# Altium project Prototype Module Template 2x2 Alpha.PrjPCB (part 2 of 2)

## Sheet Host Comm.SchDoc: Host Communication
size B; Date: 12/18/2013; DrawnBy: David McCoy; Engineer: David McCoy (Cospan Design); DocumentNumber: 9; Revision: C; SheetNumber: 9; SheetTotal: 10

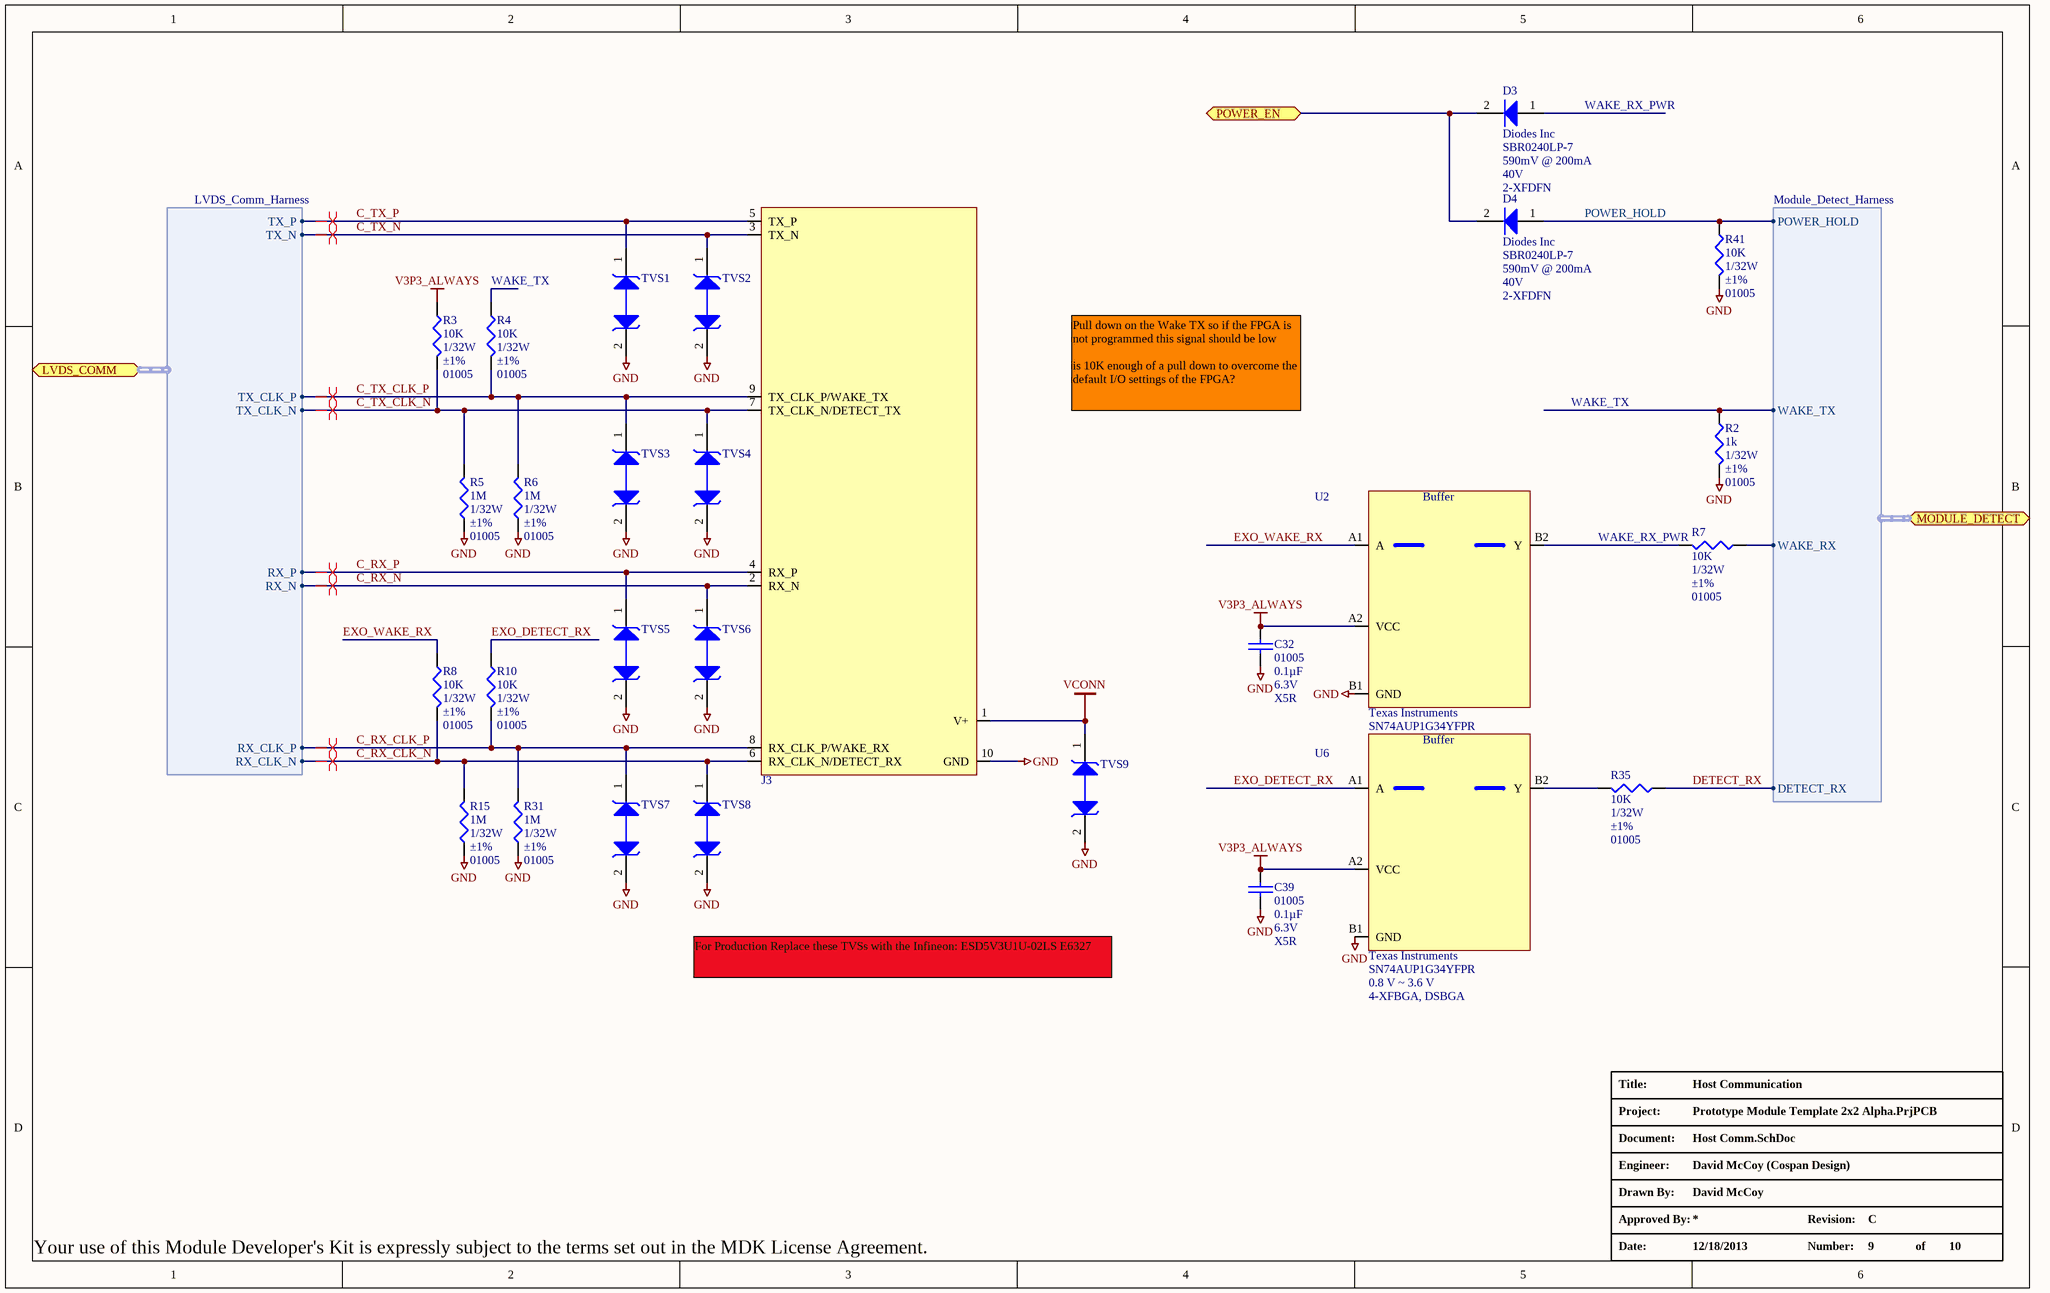
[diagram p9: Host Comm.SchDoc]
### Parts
C32  Package / Case: 01005  Capacitance: 0.1µF  Voltage - Rated: 6.3V  Temperature Coefficient: X5R  [C_01005]  (hidden comment: 0.1uF)
C39  Package / Case: 01005  Capacitance: 0.1µF  Voltage - Rated: 6.3V  Temperature Coefficient: X5R  [C_01005]  (hidden comment: 0.1uF)
D3  Manufacturer: Diodes Inc  Voltage - Forward (Vf) (Max) @ If: 590mV @ 200mA  Voltage - DC Reverse (Vr) (Max): 40V  [2-XFDFN]  (hidden comment: SBR0240LP-7)
D4  Manufacturer: Diodes Inc  Voltage - Forward (Vf) (Max) @ If: 590mV @ 200mA  Voltage - DC Reverse (Vr) (Max): 40V  [2-XFDFN]  (hidden comment: SBR0240LP-7)
J3  SPRING PIN  [10PIN SMD CONNECTOR]  (value not drawn)  (no BOM)
R2  Power (Watts): 1/32W  Tolerance: ±1%  Case: 01005  [R_01005]  (hidden comment: 1k)
R3  Power (Watts): 1/32W  Tolerance: ±1%  Case: 01005  [R_01005]  (hidden comment: 10K)
R4  Power (Watts): 1/32W  Tolerance: ±1%  Case: 01005  [R_01005]  (hidden comment: 10K)
R5  Resistance In Ohms: 1M  Power (Watts): 1/32W  Tolerance: ±1%  Case: 01005  [R_01005]  (hidden comment: 1M Ohms)
R6  Resistance In Ohms: 1M  Power (Watts): 1/32W  Tolerance: ±1%  Case: 01005  [R_01005]  (hidden comment: 1M Ohms)
R7  Power (Watts): 1/32W  Tolerance: ±1%  Case: 01005  [R_01005]  (hidden comment: 10K)
R8  Power (Watts): 1/32W  Tolerance: ±1%  Case: 01005  [R_01005]  (hidden comment: 10K)
R10  Power (Watts): 1/32W  Tolerance: ±1%  Case: 01005  [R_01005]  (hidden comment: 10K)
R15  Resistance In Ohms: 1M  Power (Watts): 1/32W  Tolerance: ±1%  Case: 01005  [R_01005]  (hidden comment: 1M Ohms)
R31  Resistance In Ohms: 1M  Power (Watts): 1/32W  Tolerance: ±1%  Case: 01005  [R_01005]  (hidden comment: 1M Ohms)
R35  Power (Watts): 1/32W  Tolerance: ±1%  Case: 01005  [R_01005]  (hidden comment: 10K)
R41  Power (Watts): 1/32W  Tolerance: ±1%  Case: 01005  [R_01005]  (hidden comment: 10K)
TVS1  TVS_ESDAVLC6-1BV2  [ST_MICRO_TVS]  (value not drawn)
TVS2  TVS_ESDAVLC6-1BV2  [ST_MICRO_TVS]  (value not drawn)
TVS3  TVS_ESDAVLC6-1BV2  [ST_MICRO_TVS]  (value not drawn)
TVS4  TVS_ESDAVLC6-1BV2  [ST_MICRO_TVS]  (value not drawn)
TVS5  TVS_ESDAVLC6-1BV2  [ST_MICRO_TVS]  (value not drawn)
TVS6  TVS_ESDAVLC6-1BV2  [ST_MICRO_TVS]  (value not drawn)
TVS7  TVS_ESDAVLC6-1BV2  [ST_MICRO_TVS]  (value not drawn)
TVS8  TVS_ESDAVLC6-1BV2  [ST_MICRO_TVS]  (value not drawn)
TVS9  TVS_ESDAVLC6-1BV2  [ST_MICRO_TVS]  (value not drawn)
U2  Manufacturer: Texas Instruments  Manufacturer Part Number: SN74AUP1G34YFPR  Voltage - Supply: 0.8 V ~ 3.6 V  Package / Case: 4-XFBGA, DSBGA  [DSBGA4_.4MM]  (hidden comment: Buffer)
U6  Manufacturer: Texas Instruments  Manufacturer Part Number: SN74AUP1G34YFPR  Voltage - Supply: 0.8 V ~ 3.6 V  Package / Case: 4-XFBGA, DSBGA  [DSBGA4_.4MM]  (hidden comment: Buffer)

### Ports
LVDS_COMM (harness LVDS_Comm_Harness), MODULE_DETECT (harness Module_Detect_Harness), POWER_EN

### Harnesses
Module_Detect_Harness: WAKE_TX, WAKE_RX, DETECT_RX, POWER_HOLD
LVDS_Comm_Harness: TX_P, TX_N, TX_CLK_P, TX_CLK_N, RX_P, RX_N, RX_CLK_P, RX_CLK_N

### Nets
GND: C32.1 C39.1 J3.10(GND) R2.1 R5.2 R6.2 R15.2 R31.2 R41.1 TVS1.2 TVS2.2 TVS3.2 TVS4.2 TVS5.2 TVS6.2 TVS7.2 TVS8.2 TVS9.2 U2.B1(GND) U6.B1(GND)
V3P3_ALWAYS: C32.2 C39.2 R3.2 U2.A2(VCC) U6.A2(VCC)
VCONN: J3.1(V+) TVS9.1
C_RX_CLK_N: J3.6(RX_CLK_N/DETECT_RX) R8.1 R15.1 TVS8.1 ; port LVDS_COMM.RX_CLK_N
C_RX_CLK_P: J3.8(RX_CLK_P/WAKE_RX) R10.1 R31.1 TVS7.1 ; port LVDS_COMM.RX_CLK_P
C_RX_N: J3.2(RX_N) TVS6.1 ; port LVDS_COMM.RX_N
C_RX_P: J3.4(RX_P) TVS5.1 ; port LVDS_COMM.RX_P
C_TX_CLK_N: J3.7(TX_CLK_N/DETECT_TX) R3.1 R5.1 TVS4.1 ; port LVDS_COMM.TX_CLK_N
C_TX_CLK_P: J3.9(TX_CLK_P/WAKE_TX) R4.1 R6.1 TVS3.1 ; port LVDS_COMM.TX_CLK_P
C_TX_N: J3.3(TX_N) TVS2.1 ; port LVDS_COMM.TX_N
C_TX_P: J3.5(TX_P) TVS1.1 ; port LVDS_COMM.TX_P
DETECT_RX: R35.2 ; port MODULE_DETECT.DETECT_RX
EXO_DETECT_RX: R10.2 U6.A1(A)
EXO_WAKE_RX: R8.2 U2.A1(A)
POWER_EN: D3.2(K) D4.2(K) ; port POWER_EN
POWER_HOLD: D4.1(A) R41.2 ; port MODULE_DETECT.POWER_HOLD
WAKE_RX: R7.2 ; port MODULE_DETECT.WAKE_RX
WAKE_RX_PWR: D3.1(A) R7.1 U2.B2(Y)
WAKE_TX: R2.2 R4.2 ; port MODULE_DETECT.WAKE_TX
NetR35_1: R35.1 U6.B2(Y)

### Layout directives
differential pair: C_RX_CLK_N, C_RX_CLK_P, C_RX_N, C_RX_P, C_TX_CLK_N, C_TX_CLK_P, C_TX_N, C_TX_P

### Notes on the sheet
- Pull down on the Wake TX so if the FPGA is not programmed this signal should be low
  is 10K enough of a pull down to overcome the default I/O settings of the FPGA?
- For Production Replace these TVSs with the Infineon: ESD5V3U1U-02LS E6327

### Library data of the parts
C32 C39 = C_01005_0.1uF: CAP CER 0.1UF 6.3V 20% X5R 01005; Manufacturer: TDK Corporation; Manufacturer Part Number: C0402X5R0J104M020BC
D3 D4 = D_SBR0240LP-7: DIODE SUP BARRIER 40V 0.25A 2DFN; Diode Type: Super Barrier; Current - Average Rectified (Io): 250mA; Speed: Fast Recovery =< 500ns, > 200mA (Io); Current - Reverse Leakage @ Vr: 10µA @ 40V; Thermal Resistance: 270°C/W Ja
J3 = J_TONKA_MODULE_CONNECTOR
R2 = R_01005_1k: RES 1K OHM 1/32W 1% 01005 SM; Manufacturer: Panasonic Electronic Components; Manufacturer Part Number: ERJ-XGNF1001Y; Temperature Coefficient: ±200ppm/°C
R3 R4 R7 R8 R10 R35 R41 = R_01005_10K: RES 10K OHM 1/32W 1% 01005; Manufacturer: Samsung Electro-Mechanics America, Inc; Manufacturer Part Number: RC0402F103CS; Temperature Coefficient: ±250ppm/°C
R5 R6 R15 R31 = R_01005_1M: RES 1M OHM 1/32W 1% 01005 SMD; Manufacturer: Yageo; Manufacturer Part Number: RC0100FR-071ML; Temperature Coefficient: ±250ppm/°C
TVS1-TVS9 = TVS_ESDAVLC6-1BV2: Single Line Bi Trans 8pF; Manufacturer: STMicroelectronics; Breakdown Voltage: 6 V; Capacitance: 7.5 pF; Clamping Voltage: 18 V; Channels: 1 Channel; Peak Pulse Power Dissipation: 45 W; Polarity: Bidirectional; Product Status: New Product
U2 U6 = U_SN74AUP1G34YFPR: IC BUFFER GATE SGL 4-DSBGA; Logic Type: Buffer/Line Driver, Non-Inverting; Number of Elements: 1; Current - Output High, Low: 4mA, 4mA

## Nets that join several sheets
GND: Block Diagram (S1.S T1.1), FPGA Banks (25 pins), FPGA Config (16 pins), FPGA Power (148 pins), Power (20 pins), EPM (30 pins), Host Comm (20 pins)
V1P2: FPGA Power (38 pins), Power (C40.2 C41.2 U11.A1)
V2P5: FPGA Banks (7 pins), Power (C82.2 L1.2 U12.C3)
V3P3: Block Diagram (T1.2), FPGA Banks (38 pins), FPGA Config (17 pins), FPGA Power (11 pins), Power (C95.2 U13.A1), EPM (C9.2 L2.1 U4.4)
V3P3_ALWAYS: Power (8 pins), Host Comm (5 pins)
VCONN: Power (7 pins), Host Comm (J3.1 TVS9.1)
C_RX_CLK_N: FPGA Banks (C90.1), Host Comm (J3.6 R8.1 R15.1 TVS8.1)
C_RX_CLK_P: FPGA Banks (C89.1), Host Comm (J3.8 R10.1 R31.1 TVS7.1)
C_RX_N: FPGA Banks (C88.1), Host Comm (J3.2 TVS6.1)
C_RX_P: FPGA Banks (C87.1), Host Comm (J3.4 TVS5.1)
C_TX_CLK_N: FPGA Banks (C86.1), Host Comm (J3.7 R3.1 R5.1 TVS4.1)
C_TX_CLK_P: FPGA Banks (C85.1), Host Comm (J3.9 R4.1 R6.1 TVS3.1)
C_TX_N: FPGA Banks (C84.1), Host Comm (J3.3 TVS2.1)
C_TX_P: FPGA Banks (C83.1), Host Comm (J3.5 TVS1.1)
DETECT_RX: FPGA Banks (U3.B13), Host Comm (R35.2)
EPM_HBA_N: FPGA Banks (U3.R18), EPM (Q3.1)
EPM_HBA_P: FPGA Banks (U3.V18), EPM (Q2.1 R59.1)
EPM_HBB_N: FPGA Banks (U3.T17), EPM (Q8.1)
EPM_HBB_P: FPGA Banks (U3.R17), EPM (Q7.1 R60.1)
EPM_HBC_N: FPGA Banks (U3.R19), EPM (Q11.1)
EPM_HBC_P: FPGA Banks (U3.T18), EPM (Q10.1 R61.1)
EPM_HBD_N: FPGA Banks (U3.P19), EPM (Q12.1)
EPM_HBD_P: FPGA Banks (U3.P17), EPM (Q9.1 R62.1)
EPM_REG_EN: FPGA Banks (U3.V19), EPM (R9.1 U4.6)
POWER_EN: Power (R1.1 U11.B2 U12.C1 U13.B2), Host Comm (D3.2 D4.2)
POWER_HOLD: FPGA Banks (U3.C13), Host Comm (D4.1 R41.2)
WAKE_RX: FPGA Banks (U3.C12), Host Comm (R7.2)
WAKE_TX: FPGA Banks (U3.A11), Host Comm (R2.2 R4.2)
